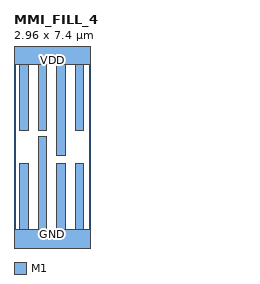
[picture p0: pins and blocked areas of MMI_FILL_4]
MACRO MMI_FILL_4
	CLASS CORE ;
	FOREIGN MMI_FILL_4 0 0 ;
	SIZE 2.96 BY 7.4 ;
	SYMMETRY X Y ;
	SITE CORE1 ;
	PIN GND
		DIRECTION inout ;
		USE GROUND ;
		PORT
			LAYER M1 ;
			RECT 0.22 0.5 0.56 3.05 ;
			LAYER M1 ;
			RECT 0.94 0.5 1.28 4.12 ;
			LAYER M1 ;
			RECT 1.66 0.5 2 3.05 ;
			LAYER M1 ;
			RECT 2.38 0.5 2.72 3.05 ;
			LAYER M1 ;
			RECT 0 -0.5 2.96 0.5 ;
		END
	END GND
	PIN VDD
		DIRECTION inout ;
		USE POWER ;
		PORT
			LAYER M1 ;
			RECT 0 6.9 2.96 7.9 ;
			LAYER M1 ;
			RECT 0.22 4.35 0.56 6.9 ;
			LAYER M1 ;
			RECT 0.94 4.35 1.28 6.9 ;
			LAYER M1 ;
			RECT 1.66 3.38 2 6.9 ;
			LAYER M1 ;
			RECT 2.38 4.35 2.72 6.9 ;
		END
	END VDD
	OBS
	END
END MMI_FILL_4
